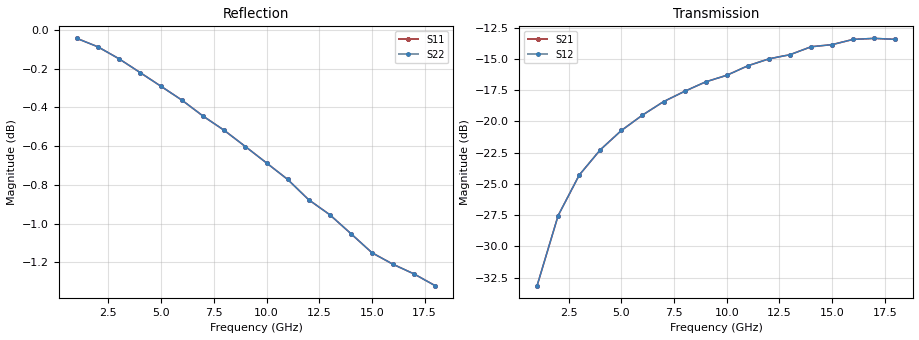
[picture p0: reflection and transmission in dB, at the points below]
!HPND-4018 beam lead PIN diode
!Series configuration S-parameters Vr=0 V.  Last updated 10/3/97
# mhz s ma r 50
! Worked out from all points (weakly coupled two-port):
!   18 points, 1 GHz to 18 GHz, reference 50 ohm
!   highest |S21| = -13.35 dB at 17 GHz (marker M1); lowest = -33.2 dB at 1 GHz (marker M2)
!   lowest |S11| = -1.3 dB at 18 GHz (marker M3), VSWR 13.18, Z = 34.1 - j138 ohm
!   |S11| at or under -10 dB: nowhere
!   |S22| runs from -1.3 to 0.0 dB; largest |S21 - S12| = 0
!   S11 on the Smith chart (normalised r, x): 1 GHz: 4, -38; 4 GHz: 2, -11; 8 GHz: 1.18, -6.09; 18 GHz: 0.68, -2.75
1000  0.995 -3.0  0.022 84.0  0.022 84.0  0.995 -3.0
2000  0.99 -5.0  0.042 76.0  0.042 76.0  0.99 -5.0
3000  0.983 -7.0  0.061 71.0  0.061 71.0  0.983 -7.0
4000  0.975 -10.0  0.077 68.0  0.077 68.0  0.975 -10.0
5000  0.967 -12.0  0.092 64.0  0.092 64.0  0.967 -12.0
6000  0.959 -14.0  0.106 62.0  0.106 62.0  0.959 -14.0
7000  0.95 -16.0  0.12 59.0  0.12 59.0  0.95 -16.0
8000  0.942 -18.0  0.132 57.0  0.132 57.0  0.942 -18.0
9000  0.933 -21.0  0.144 54.0  0.144 54.0  0.933 -21.0
10000  0.924 -23.0  0.153 52.0  0.153 52.0  0.924 -23.0
11000  0.915 -25.0  0.167 49.0  0.167 49.0  0.915 -25.0
12000  0.904 -27.0  0.178 48.0  0.178 48.0  0.904 -27.0
13000  0.896 -29.0  0.185 45.0  0.185 45.0  0.896 -29.0
14000  0.886 -31.0  0.199 43.0  0.199 43.0  0.886 -31.0
15000  0.876 -33.0  0.203 41.0  0.203 41.0  0.876 -33.0
16000  0.87 -35.0  0.213 37.0  0.213 37.0  0.87 -35.0
17000  0.865 -36.0  0.215 35.0  0.215 35.0  0.865 -36.0
18000  0.859 -38.0  0.213 32.0  0.213 32.0  0.859 -38.0
